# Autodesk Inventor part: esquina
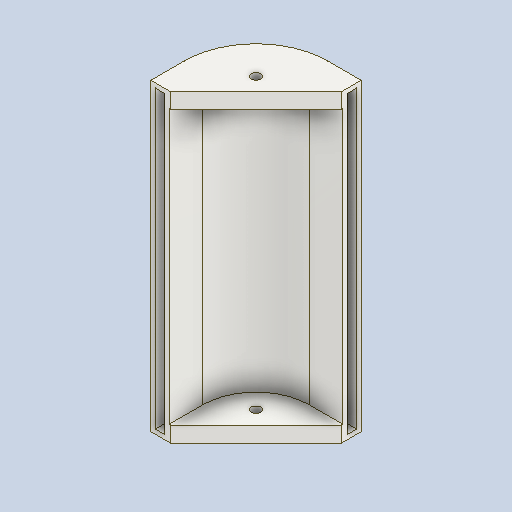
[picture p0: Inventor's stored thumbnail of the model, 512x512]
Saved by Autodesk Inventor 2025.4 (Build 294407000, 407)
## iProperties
Created: 2026-06
Part Number: esquina
Material: Generic
Document SubType Name: Modeling
Designer: AdminForWorker
Density: 1 g/cm^3
Appearance: Default
Title: esquina
Author: AdminForWorker
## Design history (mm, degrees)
feature "esquina"
body "Solid1"
